VERSION 5.8 ;
BUSBITCHARS "[]" ;
DIVIDERCHAR "|" ;
FIXEDMASK ;
USEMINSPACING OBS OFF ;
CLEARANCEMEASURE MAXXY ;

UNITS
   DATABASE MICRONS 2000 ;
   FREQUENCY MEGAHERTZ 10 ;
END UNITS

MANUFACTURINGGRID 0.005 ;

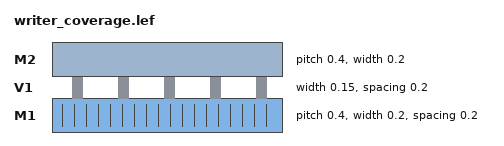
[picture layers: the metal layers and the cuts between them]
LAYER M1
   TYPE ROUTING ;
   DIRECTION VERTICAL ;
   WIDTH 0.2 ;
   PITCH 0.4 ;
   DIAGPITCH 0.5 0.6 ;
   SPACING 0.2 RANGE 0.1 0.3 USELENGTHTHRESHOLD ;
   SPACING 0.21 RANGE 0.1 0.3 RANGE 0.4 0.5 ;
   SHRINKAGE 0.1 ;
   CAPMULTIPLIER 2 ;
   EDGECAPACITANCE 0.003 ;
   ANTENNACUMAREARATIO 100 ;
   ANTENNAAREAFACTOR 2 DIFFUSEONLY ;
   ANTENNACUMSIDEAREARATIO 50 ;
   ANTENNASIDEAREAFACTOR 3 DIFFUSEONLY ;
   ANTENNADIFFAREARATIO 10 ;
   ANTENNACUMDIFFAREARATIO PWL ( ( 0 1 ) ( 1 2 ) ) ;
   ANTENNADIFFSIDEAREARATIO PWL ( ( 0 1 ) ( 2 3 ) ) ;
   ANTENNACUMDIFFSIDEAREARATIO 30 ;
END M1

LAYER V1
   TYPE CUT ;
   MASK 2 ;
   WIDTH 0.15 ;
   SPACING 0.2 AREA 0.05 ;
   ENCLOSURE BELOW 0.01 0.02 LENGTH 0.5 ;
END V1

LAYER M2
   TYPE ROUTING ;
   DIRECTION DIAG135 ;
   WIDTH 0.2 ;
   PITCH 0.4 ;
   ANTENNACUMDIFFAREARATIO 20 ;
   ANTENNADIFFSIDEAREARATIO 40 ;
   ANTENNACUMDIFFSIDEAREARATIO PWL ( ( 0 1 ) ( 3 4 ) ) ;
END M2

MAXVIASTACK 4 RANGE M1 M2 ;

VIA VIA1
   LAYER M1 ;
      RECT -1 -1 1 1 ;
   LAYER V1 ;
      RECT -0.5 -0.5 0.5 0.5 ;
END VIA1

VIARULE VIARULE1 GENERATE DEFAULT
   LAYER M1 ;
      ENCLOSURE 0.1 0.15 ;
      WIDTH 0.1 TO 1.9 ;
   LAYER M2 ;
      ENCLOSURE 0.1 0.15 ;
      WIDTH 0.1 TO 1.9 ;
   LAYER V1 ;
      RECT -0.1 -0.1 0.1 0.1 ;
      SPACING 0.5 BY 0.5 ;
END VIARULE1

NONDEFAULTRULE WIDE
   LAYER M1
      WIDTH 0.3 ;
      SPACING 0.25 ;
   END M1
   VIA ND_VIA1
      LAYER M1 ;
         RECT -1 -1 1 1 ;
      LAYER V1 ;
         RECT -0.5 -0.5 0.5 0.5 ;
   END ND_VIA1
   USEVIARULE VIARULE1 ;
END WIDE

SITE CORE
   CLASS CORE ;
   SIZE 0.2 BY 2.0 ;
   SYMMETRY X Y R90 ;
END CORE

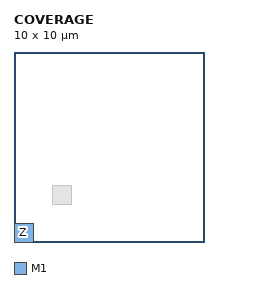
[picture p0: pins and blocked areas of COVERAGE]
MACRO COVERAGE
   CLASS CORE ;
   FOREIGN COVS 0 0 S ;
   FOREIGN COVE 0 0 E ;
   FOREIGN COVW 0 0 W ;
   FOREIGN COVFE 1 1 FE ;
   FOREIGN COVFW 2 2 FW ;
   ORIGIN 0 0 ;
   SIZE 10 BY 10 ;
   SYMMETRY X Y R90 ;
   SITE CORE ;

   PIN IO
      DIRECTION INOUT ;
      PORT
         LAYER M1 ;
            POLYGON ITERATE 0 0 1 0 1 1 0 1
               DO 2 BY 1 STEP 2 0 ;
            VIA ITERATE 5 5 VIA1
               DO 2 BY 2 STEP 1 1 ;
      END
   END IO

   PIN Z
      DIRECTION OUTPUT TRISTATE ;
      PORT
         LAYER M1 ;
            RECT 0 0 1 1 ;
      END
   END Z

   OBS
      LAYER M1 DESIGNRULEWIDTH 0.3 ;
         RECT 2 2 3 3 ;
      LAYER M1 ;
         VIA ITERATE 6 6 VIA1
            DO 1 BY 2 STEP 0 1 ;
   END
END COVERAGE
